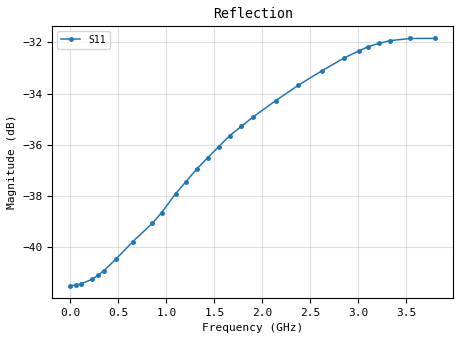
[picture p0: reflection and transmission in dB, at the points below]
! ListType=Lin
!!SAA-2 male load 0.1 to 3800MHz 500 points
# MHz S RI R 50
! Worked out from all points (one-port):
!   500 points, 100 kHz to 3.8 GHz, reference 50 ohm
!   lowest |S11| = -41.5 dB at 100 kHz (marker M1), VSWR 1.02, Z = 50.8 + j0.00761 ohm
!   |S11| at or under -10 dB: start of sweep to end of sweep
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0.1  0.00841 7.48e-05
53.40521  0.00842 -0.000433
114.3255  0.00842 -0.00102
228.5509  0.0084 -0.00212
289.4711  0.00839 -0.00272
350.3914  0.00837 -0.00332
479.8469  0.0083 -0.00462
647.3776  0.0081 -0.00627
852.9834  0.00754 -0.00819
951.9788  0.00726 -0.00916
1096.664  0.00689 -0.0107
1203.275  0.00658 -0.0117
1317.5  0.0062 -0.0128
1431.726  0.00578 -0.0138
1545.951  0.00531 -0.0148
1660.177  0.00481 -0.0158
1782.017  0.00422 -0.0167
1903.858  0.00358 -0.0176
2139.923  0.00225 -0.0192
2375.989  0.000976 -0.0207
2619.67  -0.000257 -0.0221
2855.736  -0.00137 -0.0234
3008.037  -0.00205 -0.0241
3099.417  -0.0025 -0.0245
3213.643  -0.00317 -0.0248
3327.868  -0.00396 -0.025
3541.089  -0.00578 -0.0249
3800  -0.00856 -0.0241
